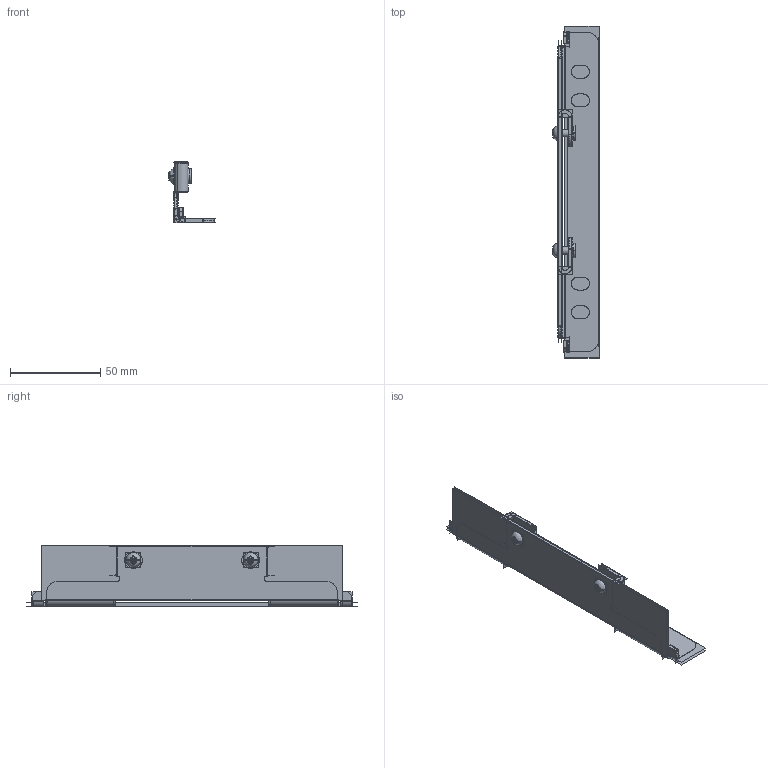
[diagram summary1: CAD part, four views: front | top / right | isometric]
IGES file: header records copied from the file, then geometry measured from it (millimetres).
Start section:  PTC IGES file: cu_bkt_rack_mount_rear_18-slot_pxi.igs
Global section: file name: cu_bkt_rack_mount_rear_18-slot_pxi.igs; native system: Creo Parametric by PTC Inc.; preprocessor: 2017480; author: talbott; organization: Unknown; date: 20180606.112251; units: millimetre
Bounding box: 25.79 x 184.08 x 34.08 mm (x, y, z)
Surface area: 39100.2 mm2 (no closed solid volume)
Topology: 0 solids, 0 shells, 484 faces, 6170 edges, 7992 vertices
Faces by surface type: bspline 320, revolution 164
